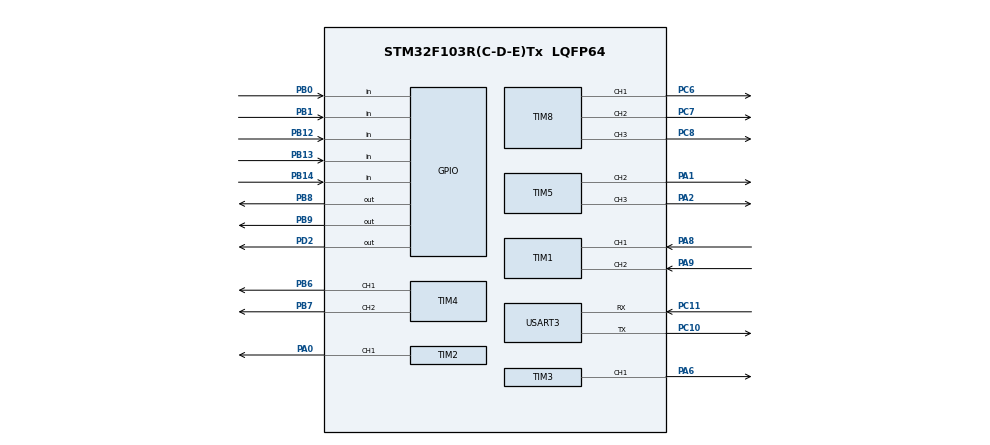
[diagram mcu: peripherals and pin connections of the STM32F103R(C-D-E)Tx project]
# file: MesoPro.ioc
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FREERTOS.Mutexes01=myMutex01,Dynamic,NULL
FREERTOS.Tasks01=defaultTask,24,128,StartDefaultTask,Default,NULL,Dynamic,NULL,NULL;myTask02,8,128,StartTask02,Default,NULL,Dynamic,NULL,NULL;myTask03,8,128,StartTask03,Default,NULL,Dynamic,NULL,NULL
FREERTOS.Timers01=myTimer01,Callback01,osTimerPeriodic,Default,NULL,Dynamic,NULL
Mcu.Family=STM32F1
Mcu.Name=STM32F103R(C-D-E)Tx
Mcu.Package=LQFP64
NVIC.PriorityGroup=NVIC_PRIORITYGROUP_4
NVIC.TIM7_IRQn=true\:0\:0\:false\:false\:true\:false\:false\:true
NVIC.TimeBase=TIM7_IRQn
NVIC.TimeBaseIP=TIM7
NVIC.USART3_IRQn=true\:5\:0\:false\:false\:true\:true\:true\:true
PA0-WKUP.Signal=S_TIM2_CH1_ETR
PA1.Signal=S_TIM5_CH2
PA2.Signal=S_TIM5_CH3
PA6.Signal=S_TIM3_CH1
PA8.Signal=S_TIM1_CH1
PA9.Signal=S_TIM1_CH2
PB0.Signal=GPIO_Input
PB1.Signal=GPIO_Input
PB12.Signal=GPIO_Input
PB13.Signal=GPIO_Input
PB14.Signal=GPIO_Input
PB6.Signal=S_TIM4_CH1
PB7.Signal=S_TIM4_CH2
PB8.Signal=GPIO_Output
PB9.Signal=GPIO_Output
PC10.Mode=Asynchronous
PC10.Signal=USART3_TX
PC11.Mode=Asynchronous
PC11.Signal=USART3_RX
PC6.Signal=S_TIM8_CH1
PC7.Signal=S_TIM8_CH2
PC8.Signal=S_TIM8_CH3
PD0-OSC_IN.Mode=HSE-External-Oscillator
PD0-OSC_IN.Signal=RCC_OSC_IN
PD1-OSC_OUT.Mode=HSE-External-Oscillator
PD1-OSC_OUT.Signal=RCC_OSC_OUT
PD2.Signal=GPIO_Output
ProjectManager.HeapSize=0x200
ProjectManager.StackSize=0x400
ProjectManager.TargetToolchain=MDK-ARM V5.27
RCC.APB1Freq_Value=8000000
RCC.APB2Freq_Value=8000000
RCC.PLLSourceVirtual=RCC_PLLSOURCE_HSE
RCC.SYSCLKSource=RCC_SYSCLKSOURCE_HSE
RCC.USBFreq_Value=16000000
SH.S_TIM1_CH1.0=TIM1_CH1,Input_Capture1_from_TI1
SH.S_TIM1_CH2.0=TIM1_CH2,Input_Capture2_from_TI2
SH.S_TIM2_CH1_ETR.0=TIM2_CH1,PWM Generation1 CH1
SH.S_TIM3_CH1.0=TIM3_CH1,PWM Generation1 CH1
SH.S_TIM4_CH1.0=TIM4_CH1,PWM Generation1 CH1
SH.S_TIM4_CH2.0=TIM4_CH2,PWM Generation2 CH2
SH.S_TIM5_CH2.0=TIM5_CH2,PWM Generation2 CH2
SH.S_TIM5_CH3.0=TIM5_CH3,PWM Generation3 CH3
SH.S_TIM8_CH1.0=TIM8_CH1,PWM Generation1 CH1
SH.S_TIM8_CH2.0=TIM8_CH2,PWM Generation2 CH2
SH.S_TIM8_CH3.0=TIM8_CH3,PWM Generation3 CH3
TIM1.Channel-Input_Capture1_from_TI1=TIM_CHANNEL_1
TIM1.Channel-Input_Capture2_from_TI2=TIM_CHANNEL_2
TIM2.Channel-PWM\ Generation1\ CH1=TIM_CHANNEL_1
TIM3.Channel-PWM\ Generation1\ CH1=TIM_CHANNEL_1
TIM4.Channel-PWM\ Generation1\ CH1=TIM_CHANNEL_1
TIM4.Channel-PWM\ Generation2\ CH2=TIM_CHANNEL_2
TIM5.Channel-PWM\ Generation2\ CH2=TIM_CHANNEL_2
TIM5.Channel-PWM\ Generation3\ CH3=TIM_CHANNEL_3
TIM8.Channel-PWM\ Generation1\ CH1=TIM_CHANNEL_1
TIM8.Channel-PWM\ Generation2\ CH2=TIM_CHANNEL_2
TIM8.Channel-PWM\ Generation3\ CH3=TIM_CHANNEL_3
USART3.VirtualMode=VM_ASYNC
VP_FREERTOS_VS_CMSIS_V2.Mode=CMSIS_V2
VP_SYS_VS_ND.Mode=No_Debug
VP_SYS_VS_tim7.Mode=TIM7
VP_TIM1_VS_ClockSourceINT.Mode=Internal
VP_TIM2_VS_ClockSourceINT.Mode=Internal
VP_TIM3_VS_ClockSourceINT.Mode=Internal
VP_TIM4_VS_ClockSourceINT.Mode=Internal
VP_TIM5_VS_ClockSourceINT.Mode=Internal
VP_TIM8_VS_ClockSourceINT.Mode=Internal
board=custom

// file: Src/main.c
/* USER CODE BEGIN Header */
/**
  ******************************************************************************
  * @file           : main.c
  * @brief          : Main program body
  ******************************************************************************
  * @attention
  *
  * <h2><center>&copy; Copyright (c) 2020 STMicroelectronics.
  * All rights reserved.</center></h2>
  *
  * This software component is licensed by ST under Ultimate Liberty license
  * SLA0044, the "License"; You may not use this file except in compliance with
  * the License. You may obtain a copy of the License at:
  *                             www.st.com/SLA0044
  *
  ******************************************************************************
  */
/* USER CODE END Header */

#include "main.h"
#include "cmsis_os.h"

TIM_HandleTypeDef htim1;
TIM_HandleTypeDef htim2;
TIM_HandleTypeDef htim3;
TIM_HandleTypeDef htim4;
TIM_HandleTypeDef htim5;
TIM_HandleTypeDef htim8;

UART_HandleTypeDef huart3;

/* Definitions for defaultTask */
osThreadId_t defaultTaskHandle;
const osThreadAttr_t defaultTask_attributes = {
  .name = "defaultTask",
  .priority = (osPriority_t) osPriorityNormal,
  .stack_size = 128 * 4
};
/* Definitions for myTask02 */
osThreadId_t myTask02Handle;
const osThreadAttr_t myTask02_attributes = {
  .name = "myTask02",
  .priority = (osPriority_t) osPriorityLow,
  .stack_size = 128 * 4
};
/* Definitions for myTask03 */
osThreadId_t myTask03Handle;
const osThreadAttr_t myTask03_attributes = {
  .name = "myTask03",
  .priority = (osPriority_t) osPriorityLow,
  .stack_size = 128 * 4
};
/* Definitions for myTimer01 */
osTimerId_t myTimer01Handle;
const osTimerAttr_t myTimer01_attributes = {
  .name = "myTimer01"
};
/* Definitions for myMutex01 */
osMutexId_t myMutex01Handle;
const osMutexAttr_t myMutex01_attributes = {
  .name = "myMutex01"
};

/* Definitions for myBinarySem01 */
osSemaphoreId_t myBinarySem01Handle;
const osSemaphoreAttr_t myBinarySem01_attributes = {
  .name = "myBinarySem01"
};

void SystemClock_Config(void);
static void MX_GPIO_Init(void);
static void MX_TIM1_Init(void);
static void MX_TIM2_Init(void);
static void MX_TIM3_Init(void);
static void MX_TIM4_Init(void);
static void MX_TIM5_Init(void);
static void MX_TIM8_Init(void);
static void MX_USART3_UART_Init(void);
void StartDefaultTask(void *argument);
void StartTask02(void *argument);
void StartTask03(void *argument);
void Callback01(void *argument);

int main(void)
{

  /* MCU Configuration--------------------------------------------------------*/

  /* Reset of all peripherals, Initializes the Flash interface and the Systick. */
  HAL_Init();

  /* Configure the system clock */
  SystemClock_Config();

  /* Initialize all configured peripherals */
  MX_GPIO_Init();
  MX_TIM1_Init();
  MX_TIM2_Init();
  MX_TIM3_Init();
  MX_TIM4_Init();
  MX_TIM5_Init();
  MX_TIM8_Init();
  MX_USART3_UART_Init();

  /* Init scheduler */
  osKernelInitialize();
  /* Create the mutex(es) */
  /* creation of myMutex01 */
  myMutex01Handle = osMutexNew(&myMutex01_attributes);

  /* USER CODE BEGIN RTOS_SEMAPHORES */
  /* add semaphores, ... */

	  myBinarySem01Handle = osSemaphoreNew(1, 0, &myBinarySem01_attributes);

  /* USER CODE END RTOS_SEMAPHORES */

  /* Create the timer(s) */
  /* creation of myTimer01 */
  myTimer01Handle = osTimerNew(Callback01, osTimerPeriodic, NULL, &myTimer01_attributes);

  /* Create the thread(s) */
  /* creation of defaultTask */
  defaultTaskHandle = osThreadNew(StartDefaultTask, NULL, &defaultTask_attributes);

  /* creation of myTask02 */
  myTask02Handle = osThreadNew(StartTask02, NULL, &myTask02_attributes);

  /* creation of myTask03 */
  myTask03Handle = osThreadNew(StartTask03, NULL, &myTask03_attributes);

  /* Start scheduler */
  osKernelStart();

  /* We should never get here as control is now taken by the scheduler */
  /* Infinite loop */
  while (1)
  {

  }
}

void SystemClock_Config(void)
{
  RCC_OscInitTypeDef RCC_OscInitStruct = {0};
  RCC_ClkInitTypeDef RCC_ClkInitStruct = {0};

  /** Initializes the CPU, AHB and APB busses clocks
  */
  RCC_OscInitStruct.OscillatorType = RCC_OSCILLATORTYPE_HSE;
  RCC_OscInitStruct.HSEState = RCC_HSE_ON;
  RCC_OscInitStruct.HSEPredivValue = RCC_HSE_PREDIV_DIV1;
  RCC_OscInitStruct.HSIState = RCC_HSI_ON;
  RCC_OscInitStruct.PLL.PLLState = RCC_PLL_ON;
  RCC_OscInitStruct.PLL.PLLSource = RCC_PLLSOURCE_HSE;
  RCC_OscInitStruct.PLL.PLLMUL = RCC_PLL_MUL9;
  if (HAL_RCC_OscConfig(&RCC_OscInitStruct) != HAL_OK)
  {
    Error_Handler();
  }
  /** Initializes the CPU, AHB and APB busses clocks
  */
  RCC_ClkInitStruct.ClockType = RCC_CLOCKTYPE_HCLK|RCC_CLOCKTYPE_SYSCLK
                              |RCC_CLOCKTYPE_PCLK1|RCC_CLOCKTYPE_PCLK2;
  RCC_ClkInitStruct.SYSCLKSource = RCC_SYSCLKSOURCE_PLLCLK;
  RCC_ClkInitStruct.AHBCLKDivider = RCC_SYSCLK_DIV1;
  RCC_ClkInitStruct.APB1CLKDivider = RCC_HCLK_DIV2;
  RCC_ClkInitStruct.APB2CLKDivider = RCC_HCLK_DIV1;

  if (HAL_RCC_ClockConfig(&RCC_ClkInitStruct, FLASH_LATENCY_2) != HAL_OK)
  {
    Error_Handler();
  }
}

static void MX_TIM1_Init(void)
{

  TIM_ClockConfigTypeDef sClockSourceConfig = {0};
  TIM_MasterConfigTypeDef sMasterConfig = {0};
  TIM_IC_InitTypeDef sConfigIC = {0};
TIM_Encoder_InitTypeDef sConfig;
  htim1.Instance = TIM1;
  htim1.Init.Prescaler = 0;
  htim1.Init.CounterMode = TIM_COUNTERMODE_UP;
  htim1.Init.Period = 60000;
  htim1.Init.ClockDivision = TIM_CLOCKDIVISION_DIV1;
  htim1.Init.RepetitionCounter = 0;
  htim1.Init.AutoReloadPreload = TIM_AUTORELOAD_PRELOAD_DISABLE;
  if (HAL_TIM_Base_Init(&htim1) != HAL_OK)
  {
    Error_Handler();
  }
  sClockSourceConfig.ClockSource = TIM_CLOCKSOURCE_TI1;
  if (HAL_TIM_ConfigClockSource(&htim1, &sClockSourceConfig) != HAL_OK)
  {
    Error_Handler();
  }

	sConfig.EncoderMode = TIM_ENCODERMODE_TI1;

	sConfig.IC1Filter = 7;
	sConfig.IC1Polarity = TIM_ENCODERINPUTPOLARITY_FALLING;
	sConfig.IC1Prescaler = TIM_ICPSC_DIV1;
	sConfig.IC1Selection = 1;
	sConfig.IC2Filter = 7;
	sConfig.IC2Polarity = TIM_ENCODERINPUTPOLARITY_FALLING;
	sConfig.IC2Prescaler = TIM_ICPSC_DIV1;
	sConfig.IC2Selection = 1;

	HAL_TIM_Encoder_Init(&htim1,  &sConfig);

  /* USER CODE BEGIN TIM1_Init 2 */
	HAL_TIM_Encoder_Start(&htim1,TIM_CHANNEL_1);
  /* USER CODE END TIM1_Init 2 */

}

static void MX_TIM2_Init(void)
{

  TIM_ClockConfigTypeDef sClockSourceConfig = {0};
  TIM_MasterConfigTypeDef sMasterConfig = {0};
  TIM_OC_InitTypeDef sConfigOC = {0};

  htim2.Instance = TIM2;
  htim2.Init.Prescaler = 360;
  htim2.Init.CounterMode = TIM_COUNTERMODE_UP;
  htim2.Init.Period = 10000 - 1;
  htim2.Init.ClockDivision = TIM_CLOCKDIVISION_DIV1;
  htim2.Init.AutoReloadPreload = TIM_AUTORELOAD_PRELOAD_DISABLE;
  if (HAL_TIM_Base_Init(&htim2) != HAL_OK)
  {
    Error_Handler();
  }
  sClockSourceConfig.ClockSource = TIM_CLOCKSOURCE_INTERNAL;
  if (HAL_TIM_ConfigClockSource(&htim2, &sClockSourceConfig) != HAL_OK)
  {
    Error_Handler();
  }
  if (HAL_TIM_PWM_Init(&htim2) != HAL_OK)
  {
    Error_Handler();
  }
  sMasterConfig.MasterOutputTrigger = TIM_TRGO_RESET;
  sMasterConfig.MasterSlaveMode = TIM_MASTERSLAVEMODE_DISABLE;
  if (HAL_TIMEx_MasterConfigSynchronization(&htim2, &sMasterConfig) != HAL_OK)
  {
    Error_Handler();
  }
  sConfigOC.OCMode = TIM_OCMODE_PWM1;
  sConfigOC.Pulse = 5000;
  sConfigOC.OCPolarity = TIM_OCPOLARITY_HIGH;
  sConfigOC.OCFastMode = TIM_OCFAST_DISABLE;
  if (HAL_TIM_PWM_ConfigChannel(&htim2, &sConfigOC, TIM_CHANNEL_1) != HAL_OK)
  {
    Error_Handler();
  }
  HAL_TIM_MspPostInit(&htim2);

}

static void MX_TIM3_Init(void)
{

  TIM_ClockConfigTypeDef sClockSourceConfig = {0};
  TIM_MasterConfigTypeDef sMasterConfig = {0};
  TIM_OC_InitTypeDef sConfigOC = {0};

  htim3.Instance = TIM3;
  htim3.Init.Prescaler = 0;
  htim3.Init.CounterMode = TIM_COUNTERMODE_UP;
  htim3.Init.Period = 0;
  htim3.Init.ClockDivision = TIM_CLOCKDIVISION_DIV1;
  htim3.Init.AutoReloadPreload = TIM_AUTORELOAD_PRELOAD_DISABLE;
  if (HAL_TIM_Base_Init(&htim3) != HAL_OK)
  {
    Error_Handler();
  }
  sClockSourceConfig.ClockSource = TIM_CLOCKSOURCE_INTERNAL;
  if (HAL_TIM_ConfigClockSource(&htim3, &sClockSourceConfig) != HAL_OK)
  {
    Error_Handler();
  }
  if (HAL_TIM_PWM_Init(&htim3) != HAL_OK)
  {
    Error_Handler();
  }
  sMasterConfig.MasterOutputTrigger = TIM_TRGO_RESET;
  sMasterConfig.MasterSlaveMode = TIM_MASTERSLAVEMODE_DISABLE;
  if (HAL_TIMEx_MasterConfigSynchronization(&htim3, &sMasterConfig) != HAL_OK)
  {
    Error_Handler();
  }
  sConfigOC.OCMode = TIM_OCMODE_PWM1;
  sConfigOC.Pulse = 0;
  sConfigOC.OCPolarity = TIM_OCPOLARITY_HIGH;
  sConfigOC.OCFastMode = TIM_OCFAST_DISABLE;
  if (HAL_TIM_PWM_ConfigChannel(&htim3, &sConfigOC, TIM_CHANNEL_1) != HAL_OK)
  {
    Error_Handler();
  }
  HAL_TIM_MspPostInit(&htim3);

}

static void MX_TIM4_Init(void)
{

  TIM_ClockConfigTypeDef sClockSourceConfig = {0};
  TIM_MasterConfigTypeDef sMasterConfig = {0};
  TIM_OC_InitTypeDef sConfigOC = {0};

  /* USER CODE BEGIN TIM4_Init 1 */
// 1MHZ
  /* USER CODE END TIM4_Init 1 */
  htim4.Instance = TIM4;
  htim4.Init.Prescaler = 0;
  htim4.Init.CounterMode = TIM_COUNTERMODE_UP;
  htim4.Init.Period = 72 - 1;
  htim4.Init.ClockDivision = TIM_CLOCKDIVISION_DIV1;
  htim4.Init.AutoReloadPreload = TIM_AUTORELOAD_PRELOAD_DISABLE;
  if (HAL_TIM_Base_Init(&htim4) != HAL_OK)
  {
    Error_Handler();
  }
  sClockSourceConfig.ClockSource = TIM_CLOCKSOURCE_INTERNAL;
  if (HAL_TIM_ConfigClockSource(&htim4, &sClockSourceConfig) != HAL_OK)
  {
    Error_Handler();
  }
  if (HAL_TIM_PWM_Init(&htim4) != HAL_OK)
  {
    Error_Handler();
  }
  sMasterConfig.MasterOutputTrigger = TIM_TRGO_RESET;
  sMasterConfig.MasterSlaveMode = TIM_MASTERSLAVEMODE_DISABLE;
  if (HAL_TIMEx_MasterConfigSynchronization(&htim4, &sMasterConfig) != HAL_OK)
  {
    Error_Handler();
  }
  sConfigOC.OCMode = TIM_OCMODE_PWM1;
  sConfigOC.Pulse = 36;
  sConfigOC.OCPolarity = TIM_OCPOLARITY_HIGH;
  sConfigOC.OCFastMode = TIM_OCFAST_DISABLE;
  if (HAL_TIM_PWM_ConfigChannel(&htim4, &sConfigOC, TIM_CHANNEL_1) != HAL_OK)
  {
    Error_Handler();
  }
  if (HAL_TIM_PWM_ConfigChannel(&htim4, &sConfigOC, TIM_CHANNEL_2) != HAL_OK)
  {
    Error_Handler();
  }
  HAL_TIM_MspPostInit(&htim4);

}

static void MX_TIM5_Init(void)
{

  TIM_ClockConfigTypeDef sClockSourceConfig = {0};
  TIM_MasterConfigTypeDef sMasterConfig = {0};
  TIM_OC_InitTypeDef sConfigOC = {0};

  /* USER CODE BEGIN TIM5_Init 1 */
  //10K HZ
  /* USER CODE END TIM5_Init 1 */
  htim5.Instance = TIM5;
  htim5.Init.Prescaler = 0;
  htim5.Init.CounterMode = TIM_COUNTERMODE_UP;
  htim5.Init.Period = 36000;
  htim5.Init.ClockDivision = TIM_CLOCKDIVISION_DIV1;
  htim5.Init.AutoReloadPreload = TIM_AUTORELOAD_PRELOAD_DISABLE;
  if (HAL_TIM_Base_Init(&htim5) != HAL_OK)
  {
    Error_Handler();
  }
  sClockSourceConfig.ClockSource = TIM_CLOCKSOURCE_INTERNAL;
  if (HAL_TIM_ConfigClockSource(&htim5, &sClockSourceConfig) != HAL_OK)
  {
    Error_Handler();
  }
  if (HAL_TIM_PWM_Init(&htim5) != HAL_OK)
  {
    Error_Handler();
  }
  sMasterConfig.MasterOutputTrigger = TIM_TRGO_RESET;
  sMasterConfig.MasterSlaveMode = TIM_MASTERSLAVEMODE_DISABLE;
  if (HAL_TIMEx_MasterConfigSynchronization(&htim5, &sMasterConfig) != HAL_OK)
  {
    Error_Handler();
  }
  sConfigOC.OCMode = TIM_OCMODE_PWM1;
  sConfigOC.Pulse = 0;
  sConfigOC.OCPolarity = TIM_OCPOLARITY_HIGH;
  sConfigOC.OCFastMode = TIM_OCFAST_DISABLE;
  if (HAL_TIM_PWM_ConfigChannel(&htim5, &sConfigOC, TIM_CHANNEL_2) != HAL_OK)
  {
    Error_Handler();
  }
  if (HAL_TIM_PWM_ConfigChannel(&htim5, &sConfigOC, TIM_CHANNEL_3) != HAL_OK)
  {
    Error_Handler();
  }
  HAL_TIM_MspPostInit(&htim5);

}

static void MX_TIM8_Init(void)
{

  TIM_ClockConfigTypeDef sClockSourceConfig = {0};
  TIM_MasterConfigTypeDef sMasterConfig = {0};
  TIM_OC_InitTypeDef sConfigOC = {0};
  TIM_BreakDeadTimeConfigTypeDef sBreakDeadTimeConfig = {0};

  /* USER CODE BEGIN TIM8_Init 1 */
// 50 HZ
  /* USER CODE END TIM8_Init 1 */
  htim8.Instance = TIM8;
  htim8.Init.Prescaler = 144;
  htim8.Init.CounterMode = TIM_COUNTERMODE_UP;
  htim8.Init.Period = 10000 - 1;
  htim8.Init.ClockDivision = TIM_CLOCKDIVISION_DIV1;
  htim8.Init.RepetitionCounter = 0;
  htim8.Init.AutoReloadPreload = TIM_AUTORELOAD_PRELOAD_DISABLE;
  if (HAL_TIM_Base_Init(&htim8) != HAL_OK)
  {
    Error_Handler();
  }
  sClockSourceConfig.ClockSource = TIM_CLOCKSOURCE_INTERNAL;
  if (HAL_TIM_ConfigClockSource(&htim8, &sClockSourceConfig) != HAL_OK)
  {
    Error_Handler();
  }
  if (HAL_TIM_PWM_Init(&htim8) != HAL_OK)
  {
    Error_Handler();
  }
  sMasterConfig.MasterOutputTrigger = TIM_TRGO_RESET;
  sMasterConfig.MasterSlaveMode = TIM_MASTERSLAVEMODE_DISABLE;
  if (HAL_TIMEx_MasterConfigSynchronization(&htim8, &sMasterConfig) != HAL_OK)
  {
    Error_Handler();
  }
  sConfigOC.OCMode = TIM_OCMODE_PWM1;
  sConfigOC.Pulse = 36;
  sConfigOC.OCPolarity = TIM_OCPOLARITY_HIGH;
  sConfigOC.OCNPolarity = TIM_OCNPOLARITY_HIGH;
  sConfigOC.OCFastMode = TIM_OCFAST_DISABLE;
  sConfigOC.OCIdleState = TIM_OCIDLESTATE_RESET;
  sConfigOC.OCNIdleState = TIM_OCNIDLESTATE_RESET;
  if (HAL_TIM_PWM_ConfigChannel(&htim8, &sConfigOC, TIM_CHANNEL_1) != HAL_OK)
  {
    Error_Handler();
  }
  if (HAL_TIM_PWM_ConfigChannel(&htim8, &sConfigOC, TIM_CHANNEL_2) != HAL_OK)
  {
    Error_Handler();
  }
  if (HAL_TIM_PWM_ConfigChannel(&htim8, &sConfigOC, TIM_CHANNEL_3) != HAL_OK)
  {
    Error_Handler();
  }
  sBreakDeadTimeConfig.OffStateRunMode = TIM_OSSR_DISABLE;
  sBreakDeadTimeConfig.OffStateIDLEMode = TIM_OSSI_DISABLE;
  sBreakDeadTimeConfig.LockLevel = TIM_LOCKLEVEL_OFF;
  sBreakDeadTimeConfig.DeadTime = 0;
  sBreakDeadTimeConfig.BreakState = TIM_BREAK_DISABLE;
  sBreakDeadTimeConfig.BreakPolarity = TIM_BREAKPOLARITY_HIGH;
  sBreakDeadTimeConfig.AutomaticOutput = TIM_AUTOMATICOUTPUT_DISABLE;
  if (HAL_TIMEx_ConfigBreakDeadTime(&htim8, &sBreakDeadTimeConfig) != HAL_OK)
  {
    Error_Handler();
  }
  HAL_TIM_MspPostInit(&htim8);

}

static void MX_USART3_UART_Init(void)
{

  huart3.Instance = USART3;
  huart3.Init.BaudRate = 115200;
  huart3.Init.WordLength = UART_WORDLENGTH_8B;
  huart3.Init.StopBits = UART_STOPBITS_1;
  huart3.Init.Parity = UART_PARITY_NONE;
  huart3.Init.Mode = UART_MODE_TX_RX;
  huart3.Init.HwFlowCtl = UART_HWCONTROL_NONE;
  huart3.Init.OverSampling = UART_OVERSAMPLING_16;
  if (HAL_UART_Init(&huart3) != HAL_OK)
  {
    Error_Handler();
  }

}

static void MX_GPIO_Init(void)
{
  GPIO_InitTypeDef GPIO_InitStruct = {0};

  /* GPIO Ports Clock Enable */
  __HAL_RCC_GPIOD_CLK_ENABLE();
  __HAL_RCC_GPIOA_CLK_ENABLE();
  __HAL_RCC_GPIOB_CLK_ENABLE();
  __HAL_RCC_GPIOC_CLK_ENABLE();

  /*Configure GPIO pin Output Level */
  HAL_GPIO_WritePin(GPIOD, GPIO_PIN_2, GPIO_PIN_RESET);

  /*Configure GPIO pin Output Level */
  HAL_GPIO_WritePin(GPIOB, GPIO_PIN_8|GPIO_PIN_9, GPIO_PIN_RESET);

  /*Configure GPIO pins : PB0 PB1 PB12 PB13
                           PB14 */
  GPIO_InitStruct.Pin = GPIO_PIN_0|GPIO_PIN_1|GPIO_PIN_12|GPIO_PIN_13
                          |GPIO_PIN_14;
  GPIO_InitStruct.Mode = GPIO_MODE_INPUT;
  GPIO_InitStruct.Pull = GPIO_NOPULL;
  HAL_GPIO_Init(GPIOB, &GPIO_InitStruct);

	  GPIO_InitStruct.Pin = GPIO_PIN_0;
  GPIO_InitStruct.Mode = GPIO_MODE_OUTPUT_PP;
  GPIO_InitStruct.Pull = GPIO_NOPULL;
	GPIO_InitStruct.Speed = GPIO_SPEED_FREQ_LOW;
  HAL_GPIO_Init(GPIOB, &GPIO_InitStruct);

  /*Configure GPIO pin : PD2 */
  GPIO_InitStruct.Pin = GPIO_PIN_2;
  GPIO_InitStruct.Mode = GPIO_MODE_OUTPUT_PP;
  GPIO_InitStruct.Pull = GPIO_NOPULL;
  GPIO_InitStruct.Speed = GPIO_SPEED_FREQ_LOW;
  HAL_GPIO_Init(GPIOD, &GPIO_InitStruct);

  /*Configure GPIO pins : PB8 PB9 */
  GPIO_InitStruct.Pin = GPIO_PIN_8|GPIO_PIN_9;
  GPIO_InitStruct.Mode = GPIO_MODE_OUTPUT_PP;
  GPIO_InitStruct.Pull = GPIO_NOPULL;
  GPIO_InitStruct.Speed = GPIO_SPEED_FREQ_LOW;
  HAL_GPIO_Init(GPIOB, &GPIO_InitStruct);

  GPIO_InitStruct.Pin = GPIO_PIN_15|GPIO_PIN_7;
  GPIO_InitStruct.Mode = GPIO_MODE_OUTPUT_PP;
  GPIO_InitStruct.Pull = GPIO_NOPULL;
  GPIO_InitStruct.Speed = GPIO_SPEED_FREQ_HIGH;
  HAL_GPIO_Init(GPIOA, &GPIO_InitStruct);

}

void StartDefaultTask(void *argument)
{
  /* USER CODE BEGIN 5 */
  /* Infinite loop */

  for(;;)
  {
		interface_task();

    osDelay(1);
  }
  /* USER CODE END 5 */
}

void StartTask02(void *argument)
{
  /* USER CODE BEGIN StartTask02 */
  /* Infinite loop */

	volatile int iswitchState;

 goRun(0);
	for(;;)
  {
		iswitchState = getPosSwitchState();

    osDelay(10);

	iswitchState = getPosSwitchState();

  }
  /* USER CODE END StartTask02 */
}

void StartTask03(void *argument)
{
  for(;;)
  {
    osDelay(1);
  }
}

/* Callback01 function */
void Callback01(void *argument)
{
}

 /**
  * @brief  Period elapsed callback in non blocking mode
  * @note   This function is called  when TIM7 interrupt took place, inside
  * HAL_TIM_IRQHandler(). It makes a direct call to HAL_IncTick() to increment
  * a global variable "uwTick" used as application time base.
  * @param  htim : TIM handle
  * @retval None
  */
void HAL_TIM_PeriodElapsedCallback(TIM_HandleTypeDef *htim)
{
  if (htim->Instance == TIM7) {
    HAL_IncTick();
  }
}

void Error_Handler(void)
{
}

/************************ (C) COPYRIGHT STMicroelectronics *****END OF FILE****/
